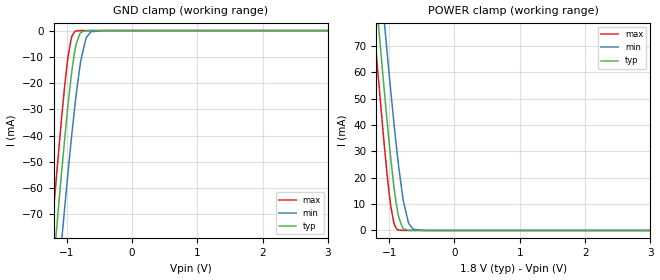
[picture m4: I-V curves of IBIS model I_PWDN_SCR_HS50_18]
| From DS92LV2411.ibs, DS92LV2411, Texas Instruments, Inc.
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|   Model I_PWDN_SCR_HS50_18
[Model] I_PWDN_SCR_HS50_18
Model_type Input
Vinl =   0.63
Vinh =   1.17
|   typ   min   max
|   (nom)   (slow)   (fast)
C_comp   0.5298pF   0.5298pF   0.5298pF
[Temperature Range]   25.000   105.000   -40.000
[Voltage Range]   1.800V   1.7100V   1.8900V
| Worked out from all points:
|   GND clamp passes 1 mA (typ) near -0.79 V on its own axis
|   POWER clamp passes 1 mA (typ) near -0.79 V on its own axis
[GND Clamp]
|   Voltage   I(typ)   I(min)   I(max)
-1.8V     -270.9mA   -291mA     -255.6mA
-1.222V   -95.51mA   -121.1mA   -75.15mA
-1.174V   -81.38mA   -107.3mA   -60.73mA
-1.076V   -53.94mA   -80.27mA   -33.21mA
-1.033V   -42.3mA    -68.56mA   -22.07mA
-973.8mV  -27.32mA   -52.95mA   -9.31mA
-925.2mV  -16.55mA   -40.77mA   -2.804mA
-865.8mV  -6.614mA   -27.03mA   -262.6uA
-779.4mV  -627.1uA   -10.99mA   -10.46uA
-703.8mV  -41.34uA   -2.997mA   -6.099uA
-628.2mV  -5.494uA   -435uA     -5.361uA
3.595V    0A         0A         0A
[POWER Clamp]
|   Voltage   I(typ)   I(min)   I(max)
-1.8V     270.2mA    290.2mA    254.9mA
-1.222V   95.2mA     120.7mA    74.88mA
-1.174V   81.1mA     107mA      60.51mA
-1.076V   53.73mA    79.99mA    33.06mA
-1.033V   42.12mA    68.31mA    21.96mA
-973.8mV  27.18mA    52.73mA    9.244mA
-925.2mV  16.45mA    40.59mA    2.782mA
-865.8mV  6.56mA     26.88mA    266.2uA
-779.4mV  623uA      10.91mA    17.92uA
-703.8mV  44.6uA     2.967mA    14.14uA
-628.2mV  9.632uA    431.2uA    13.91uA
3.595V    0A         0A         0A
